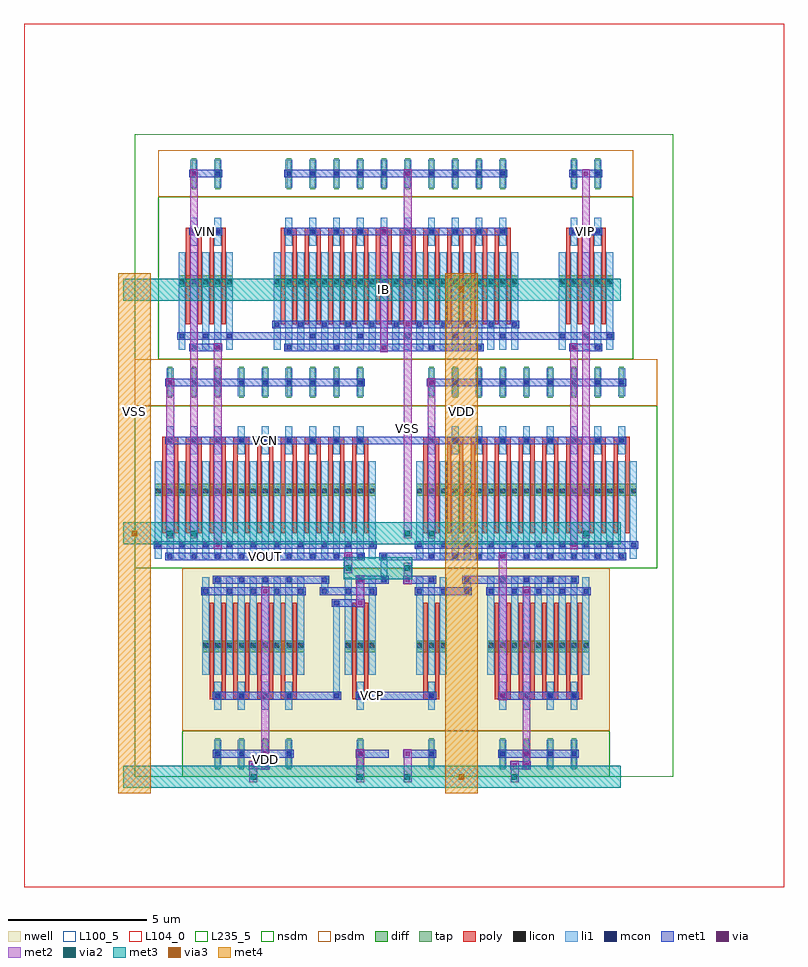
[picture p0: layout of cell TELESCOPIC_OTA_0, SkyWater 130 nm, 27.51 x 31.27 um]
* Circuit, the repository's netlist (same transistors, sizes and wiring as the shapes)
* NGSPICE file created from TELESCOPIC_OTA_0.ext - technology: sky130A

.subckt NMOS_4T_14241495_X2_Y1_1774869423 a_147_525# a_200_252# a_241_1232# a_230_525#
X0 a_230_525# a_200_252# a_147_525# a_241_1232# sky130_fd_pr__nfet_01v8 ad=0.0588 pd=0.7 as=0.0588 ps=0.7 w=0.42 l=0.15 M=4
.ends

.subckt PMOS_S_70514696_X4_Y1_1774869426 a_200_252# w_0_0# a_230_525#
X0 w_0_0# a_200_252# a_230_525# w_0_0# sky130_fd_pr__pfet_01v8 ad=0.0588 pd=0.7 as=0.0588 ps=0.7 w=0.42 l=0.15 M=8
.ends

.subckt NMOS_4T_34206428_X9_Y1_1774869424 a_147_525# a_200_252# a_241_1232# a_230_525#
X0 a_230_525# a_200_252# a_147_525# a_241_1232# sky130_fd_pr__nfet_01v8 ad=0.0588 pd=0.7 as=0.0588 ps=0.7 w=0.42 l=0.15 M=18
.ends

.subckt PMOS_4T_68898473_X1_Y1_1774869425 a_147_525# a_200_252# w_0_0# a_230_525#
X0 a_230_525# a_200_252# a_147_525# w_0_0# sky130_fd_pr__pfet_01v8 ad=0.0588 pd=0.7 as=0.1113 ps=1.37 w=0.42 l=0.15 M=2
.ends

.subckt SCM_NMOS_19423653_X5_Y1_1774869427 a_402_525# a_147_525# a_200_252#
X0 a_402_525# a_200_252# a_147_525# a_147_525# sky130_fd_pr__nfet_01v8 ad=0.0588 pd=0.7 as=0.0588 ps=0.7 w=0.42 l=0.15 M=10
X1 a_200_252# a_200_252# a_147_525# a_147_525# sky130_fd_pr__nfet_01v8 ad=0.0588 pd=0.7 as=0.0588 ps=0.7 w=0.42 l=0.15 M=10
.ends

.subckt TELESCOPIC_OTA_0 IB VCN VOUT VIP VIN VCP VSS VDD
XNMOS_4T_14241495_X2_Y1_1774869423_0 m1_688_3164# VIN VSS m1_570_1652# NMOS_4T_14241495_X2_Y1_1774869423
XNMOS_4T_14241495_X2_Y1_1774869423_1 m1_688_3164# VIP VSS m1_3150_1652# NMOS_4T_14241495_X2_Y1_1774869423
XPMOS_S_70514696_X4_Y1_1774869426_0 m1_2634_560# VDD li_2383_1327# PMOS_S_70514696_X4_Y1_1774869426
XPMOS_S_70514696_X4_Y1_1774869426_1 m1_2634_560# VDD li_1351_1327# PMOS_S_70514696_X4_Y1_1774869426
XNMOS_4T_34206428_X9_Y1_1774869424_0 m1_570_1652# VCN VSS VOUT NMOS_4T_34206428_X9_Y1_1774869424
XNMOS_4T_34206428_X9_Y1_1774869424_1 m1_3150_1652# VCN VSS m1_2634_560# NMOS_4T_34206428_X9_Y1_1774869424
XPMOS_4T_68898473_X1_Y1_1774869425_0 li_2383_1327# VCP VDD VOUT PMOS_4T_68898473_X1_Y1_1774869425
XPMOS_4T_68898473_X1_Y1_1774869425_1 li_1351_1327# VCP VDD m1_2634_560# PMOS_4T_68898473_X1_Y1_1774869425
XSCM_NMOS_19423653_X5_Y1_1774869427_0 m1_688_3164# VSS IB SCM_NMOS_19423653_X5_Y1_1774869427
.ends

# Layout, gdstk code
from math import pi, radians
import gdstk
lib = gdstk.Library(unit=1e-6, precision=1e-09)
def R(c, l, rs):  # rectangles x0, y0, x1, y1
    for r in rs: c.add(gdstk.rectangle(r[:2], r[2:], *l))
def A(c, l, x, y, w, h, nx, ny, dx, dy):  # array of equal rectangles
    R(c, l, [(x+i*dx, y+j*dy, x+i*dx+w, y+j*dy+h) for i in range(nx) for j in range(ny)])
def P(c, l, *ps):  # polygons
    for p in ps: c.add(gdstk.Polygon(p, *l))
nwell = (64, 20)
diff = (65, 20)
tap = (65, 44)
poly = (66, 20)
licon = (66, 44)
li1 = (67, 20)
mcon = (67, 44)
met1 = (68, 20)
via = (68, 44)
met2 = (69, 20)
via2 = (69, 44)
met3 = (70, 20)
via3 = (70, 44)
met4 = (71, 20)
nsdm = (93, 44)
psdm = (94, 20)
L100_5 = (100, 5)
L104_0 = (104, 0)
L235_5 = (235, 5)

scm_nmos_19423653_x5_y1_ = lib.new_cell('SCM_NMOS_19423653_X5_Y1_1774869427')
R(scm_nmos_19423653_x5_y1_, diff, [(0.735,2.625,9.585,3.045)])
A(scm_nmos_19423653_x5_y1_, tap, 1.205, 6.16, 0.17, 1.12, 10, 1, 0.86, 0)
A(scm_nmos_19423653_x5_y1_, poly, 1, 1.26, 0.15, 3.36, 20, 1, 0.43, 0)
A(scm_nmos_19423653_x5_y1_, poly, 1, 4.485, 0.58, 0.27, 10, 1, 0.86, 0)
A(scm_nmos_19423653_x5_y1_, licon, 0.775, 2.705, 0.17, 0.17, 3, 1, 0.43, 0)
A(scm_nmos_19423653_x5_y1_, licon, 1.635, 2.705, 0.17, 0.17, 3, 1, 0.43, 0)
A(scm_nmos_19423653_x5_y1_, licon, 2.495, 2.705, 0.17, 0.17, 3, 1, 0.43, 0)
A(scm_nmos_19423653_x5_y1_, licon, 3.355, 2.705, 0.17, 0.17, 3, 1, 0.43, 0)
A(scm_nmos_19423653_x5_y1_, licon, 4.215, 2.705, 0.17, 0.17, 3, 1, 0.43, 0)
A(scm_nmos_19423653_x5_y1_, licon, 5.075, 2.705, 0.17, 0.17, 3, 1, 0.43, 0)
A(scm_nmos_19423653_x5_y1_, licon, 5.935, 2.705, 0.17, 0.17, 3, 1, 0.43, 0)
A(scm_nmos_19423653_x5_y1_, licon, 6.795, 2.705, 0.17, 0.17, 3, 1, 0.43, 0)
A(scm_nmos_19423653_x5_y1_, licon, 7.655, 2.705, 0.17, 0.17, 3, 1, 0.43, 0)
A(scm_nmos_19423653_x5_y1_, licon, 8.515, 2.705, 0.17, 0.17, 3, 1, 0.43, 0)
A(scm_nmos_19423653_x5_y1_, licon, 1.205, 4.535, 0.17, 0.17, 10, 2, 0.86, 2.1)
A(scm_nmos_19423653_x5_y1_, li1, 0.735, 0.335, 0.25, 3.53, 21, 1, 0.43, 0)
A(scm_nmos_19423653_x5_y1_, li1, 1.165, 4.115, 0.25, 1.01, 10, 2, 0.86, 2.1)
A(scm_nmos_19423653_x5_y1_, mcon, 1.205, 0.335, 0.17, 0.17, 5, 1, 1.72, 0)
A(scm_nmos_19423653_x5_y1_, mcon, 2.065, 0.755, 0.17, 0.17, 5, 1, 1.72, 0)
A(scm_nmos_19423653_x5_y1_, mcon, 0.775, 1.175, 0.17, 0.17, 11, 1, 0.86, 0)
A(scm_nmos_19423653_x5_y1_, mcon, 1.205, 4.535, 0.17, 0.17, 10, 2, 0.86, 2.1)
R(scm_nmos_19423653_x5_y1_, met1, [(1.12,0.28,8.34,0.56), (1.98,0.7,9.2,0.98), (0.69,1.12,9.63,1.4), (1.12,4.48,9.2,4.76), (1.12,6.58,9.2,6.86)])
R(scm_nmos_19423653_x5_y1_, via, [(4.655,0.345,4.805,0.495), (5.515,1.185,5.665,1.335), (4.655,4.545,4.805,4.695), (5.515,6.645,5.665,6.795)])
R(scm_nmos_19423653_x5_y1_, met2, [(4.59,0.26,4.87,4.78), (5.45,1.1,5.73,6.88)])
R(scm_nmos_19423653_x5_y1_, nsdm, [(0,0,10.32,5.88)])
R(scm_nmos_19423653_x5_y1_, psdm, [(0,5.88,10.32,7.56)])
R(scm_nmos_19423653_x5_y1_, L100_5, [(0,0,10.32,7.56)])

pmos_s_70514696_x4_y1_17 = lib.new_cell('PMOS_S_70514696_X4_Y1_1774869426')
R(pmos_s_70514696_x4_y1_17, nwell, [(0,0,5.16,7.56)])
R(pmos_s_70514696_x4_y1_17, diff, [(0.735,2.625,4.425,3.045)])
A(pmos_s_70514696_x4_y1_17, tap, 1.205, 6.16, 0.17, 1.12, 4, 1, 0.86, 0)
A(pmos_s_70514696_x4_y1_17, poly, 1, 1.26, 0.15, 3.36, 8, 1, 0.43, 0)
A(pmos_s_70514696_x4_y1_17, poly, 1, 4.485, 0.58, 0.27, 4, 1, 0.86, 0)
A(pmos_s_70514696_x4_y1_17, licon, 0.775, 2.705, 0.17, 0.17, 3, 1, 0.43, 0)
A(pmos_s_70514696_x4_y1_17, licon, 1.635, 2.705, 0.17, 0.17, 3, 1, 0.43, 0)
A(pmos_s_70514696_x4_y1_17, licon, 2.495, 2.705, 0.17, 0.17, 3, 1, 0.43, 0)
A(pmos_s_70514696_x4_y1_17, licon, 3.355, 2.705, 0.17, 0.17, 3, 1, 0.43, 0)
A(pmos_s_70514696_x4_y1_17, licon, 1.205, 4.535, 0.17, 0.17, 4, 2, 0.86, 2.1)
A(pmos_s_70514696_x4_y1_17, li1, 0.735, 0.335, 0.25, 3.53, 9, 1, 0.43, 0)
A(pmos_s_70514696_x4_y1_17, li1, 1.165, 4.115, 0.25, 1.01, 4, 2, 0.86, 2.1)
A(pmos_s_70514696_x4_y1_17, mcon, 1.205, 0.335, 0.17, 0.17, 4, 2, 0.86, 4.2)
A(pmos_s_70514696_x4_y1_17, mcon, 0.775, 0.755, 0.17, 0.17, 5, 1, 0.86, 0)
A(pmos_s_70514696_x4_y1_17, mcon, 1.205, 6.635, 0.17, 0.17, 4, 1, 0.86, 0)
R(pmos_s_70514696_x4_y1_17, met1, [(1.12,0.28,4.04,0.56), (0.69,0.7,4.47,0.98), (1.12,4.48,4.04,4.76), (1.12,6.58,4.04,6.86)])
R(pmos_s_70514696_x4_y1_17, via, [(2.935,0.765,3.085,0.915), (2.935,6.645,3.085,6.795)])
R(pmos_s_70514696_x4_y1_17, met2, [(2.87,0.68,3.15,6.88)])
R(pmos_s_70514696_x4_y1_17, nsdm, [(0,5.88,5.16,7.56)])
R(pmos_s_70514696_x4_y1_17, psdm, [(0,0,5.16,5.88)])
R(pmos_s_70514696_x4_y1_17, L100_5, [(0,0,5.16,7.56)])

nmos_4t_34206428_x9_y1_1 = lib.new_cell('NMOS_4T_34206428_X9_Y1_1774869424')
R(nmos_4t_34206428_x9_y1_1, diff, [(0.735,2.625,8.725,3.045)])
A(nmos_4t_34206428_x9_y1_1, tap, 1.205, 6.16, 0.17, 1.12, 9, 1, 0.86, 0)
A(nmos_4t_34206428_x9_y1_1, poly, 1, 1.26, 0.15, 3.36, 18, 1, 0.43, 0)
A(nmos_4t_34206428_x9_y1_1, poly, 1, 4.485, 0.58, 0.27, 9, 1, 0.86, 0)
A(nmos_4t_34206428_x9_y1_1, licon, 0.775, 2.705, 0.17, 0.17, 3, 1, 0.43, 0)
A(nmos_4t_34206428_x9_y1_1, licon, 1.635, 2.705, 0.17, 0.17, 3, 1, 0.43, 0)
A(nmos_4t_34206428_x9_y1_1, licon, 2.495, 2.705, 0.17, 0.17, 3, 1, 0.43, 0)
A(nmos_4t_34206428_x9_y1_1, licon, 3.355, 2.705, 0.17, 0.17, 3, 1, 0.43, 0)
A(nmos_4t_34206428_x9_y1_1, licon, 4.215, 2.705, 0.17, 0.17, 3, 1, 0.43, 0)
A(nmos_4t_34206428_x9_y1_1, licon, 5.075, 2.705, 0.17, 0.17, 3, 1, 0.43, 0)
A(nmos_4t_34206428_x9_y1_1, licon, 5.935, 2.705, 0.17, 0.17, 3, 1, 0.43, 0)
A(nmos_4t_34206428_x9_y1_1, licon, 6.795, 2.705, 0.17, 0.17, 3, 1, 0.43, 0)
A(nmos_4t_34206428_x9_y1_1, licon, 7.655, 2.705, 0.17, 0.17, 3, 1, 0.43, 0)
A(nmos_4t_34206428_x9_y1_1, licon, 1.205, 4.535, 0.17, 0.17, 9, 2, 0.86, 2.1)
A(nmos_4t_34206428_x9_y1_1, li1, 0.735, 0.335, 0.25, 3.53, 19, 1, 0.43, 0)
A(nmos_4t_34206428_x9_y1_1, li1, 1.165, 4.115, 0.25, 1.01, 9, 2, 0.86, 2.1)
A(nmos_4t_34206428_x9_y1_1, mcon, 1.205, 0.335, 0.17, 0.17, 9, 2, 0.86, 4.2)
A(nmos_4t_34206428_x9_y1_1, mcon, 0.775, 0.755, 0.17, 0.17, 10, 1, 0.86, 0)
A(nmos_4t_34206428_x9_y1_1, mcon, 1.205, 6.635, 0.17, 0.17, 9, 1, 0.86, 0)
R(nmos_4t_34206428_x9_y1_1, met1, [(1.12,0.28,8.34,0.56), (0.69,0.7,8.77,0.98), (1.12,4.48,8.34,4.76), (1.12,6.58,8.34,6.86)])
R(nmos_4t_34206428_x9_y1_1, nsdm, [(0,0,9.46,5.88)])
R(nmos_4t_34206428_x9_y1_1, psdm, [(0,5.88,9.46,7.56)])
R(nmos_4t_34206428_x9_y1_1, L100_5, [(0,0,9.46,7.56)])

nmos_4t_14241495_x2_y1_1 = lib.new_cell('NMOS_4T_14241495_X2_Y1_1774869423')
R(nmos_4t_14241495_x2_y1_1, diff, [(0.735,2.625,2.705,3.045)])
R(nmos_4t_14241495_x2_y1_1, tap, [(1.205,6.16,1.375,7.28), (2.065,6.16,2.235,7.28)])
A(nmos_4t_14241495_x2_y1_1, poly, 1, 1.26, 0.15, 3.36, 4, 1, 0.43, 0)
R(nmos_4t_14241495_x2_y1_1, poly, [(1,4.485,1.58,4.755), (1.86,4.485,2.44,4.755)])
A(nmos_4t_14241495_x2_y1_1, licon, 0.775, 2.705, 0.17, 0.17, 3, 1, 0.43, 0)
A(nmos_4t_14241495_x2_y1_1, licon, 1.635, 2.705, 0.17, 0.17, 3, 1, 0.43, 0)
R(nmos_4t_14241495_x2_y1_1, licon, [(1.205,4.535,1.375,4.705), (2.065,4.535,2.235,4.705), (1.205,6.635,1.375,6.805), (2.065,6.635,2.235,6.805)])
A(nmos_4t_14241495_x2_y1_1, li1, 0.735, 0.335, 0.25, 3.53, 5, 1, 0.43, 0)
R(nmos_4t_14241495_x2_y1_1, li1, [(1.165,4.115,1.415,5.125), (2.025,4.115,2.275,5.125), (1.165,6.215,1.415,7.225), (2.025,6.215,2.275,7.225)])
A(nmos_4t_14241495_x2_y1_1, mcon, 0.775, 0.755, 0.17, 0.17, 3, 1, 0.86, 0)
R(nmos_4t_14241495_x2_y1_1, mcon, [(1.205,0.335,1.375,0.505), (2.065,0.335,2.235,0.505), (1.205,4.535,1.375,4.705), (2.065,4.535,2.235,4.705), (1.205,6.635,1.375,6.805), (2.065,6.635,2.235,6.805)])
R(nmos_4t_14241495_x2_y1_1, met1, [(1.12,0.28,2.32,0.56), (0.69,0.7,2.75,0.98), (1.12,4.48,2.32,4.76), (1.12,6.58,2.32,6.86)])
R(nmos_4t_14241495_x2_y1_1, nsdm, [(0,0,3.44,5.88)])
R(nmos_4t_14241495_x2_y1_1, psdm, [(0,5.88,3.44,7.56)])
R(nmos_4t_14241495_x2_y1_1, L100_5, [(0,0,3.44,7.56)])

pmos_4t_68898473_x1_y1_1 = lib.new_cell('PMOS_4T_68898473_X1_Y1_1774869425')
R(pmos_4t_68898473_x1_y1_1, nwell, [(0,0,2.58,7.56)])
R(pmos_4t_68898473_x1_y1_1, diff, [(0.735,2.625,1.845,3.045)])
R(pmos_4t_68898473_x1_y1_1, tap, [(1.205,6.16,1.375,7.28)])
R(pmos_4t_68898473_x1_y1_1, poly, [(1,1.26,1.15,4.62), (1.43,1.26,1.58,4.62), (1,4.485,1.58,4.755)])
A(pmos_4t_68898473_x1_y1_1, licon, 0.775, 2.705, 0.17, 0.17, 3, 1, 0.43, 0)
R(pmos_4t_68898473_x1_y1_1, licon, [(1.205,4.535,1.375,4.705), (1.205,6.635,1.375,6.805)])
A(pmos_4t_68898473_x1_y1_1, li1, 0.735, 0.335, 0.25, 3.53, 3, 1, 0.43, 0)
R(pmos_4t_68898473_x1_y1_1, li1, [(1.165,4.115,1.415,5.125), (1.165,6.215,1.415,7.225)])
R(pmos_4t_68898473_x1_y1_1, mcon, [(1.205,0.335,1.375,0.505), (0.775,0.755,0.945,0.925), (1.635,0.755,1.805,0.925), (1.205,4.535,1.375,4.705), (1.205,6.635,1.375,6.805)])
R(pmos_4t_68898473_x1_y1_1, met1, [(0.26,0.28,1.46,0.56), (0.69,0.7,1.89,0.98), (0.26,4.48,1.46,4.76), (0.26,6.58,1.46,6.86)])
R(pmos_4t_68898473_x1_y1_1, nsdm, [(0,5.88,2.58,7.56)])
R(pmos_4t_68898473_x1_y1_1, psdm, [(0,0,2.58,5.88)])
R(pmos_4t_68898473_x1_y1_1, L100_5, [(0,0,2.58,7.56)])

telescopic_ota_0 = lib.new_cell('TELESCOPIC_OTA_0')
R(telescopic_ota_0, li1, [(7.185,2.855,7.435,3.025), (7.185,2.855,7.435,3.025), (7.185,2.855,7.435,3.025), (7.185,2.855,7.435,3.025), (7.185,2.855,7.435,3.025), (7.185,2.855,7.435,3.025), (7.185,2.94,7.435,6.3), (7.185,6.215,7.435,6.385), (7.185,6.215,7.435,6.385), (7.185,6.215,7.435,6.385), (7.185,6.215,7.435,6.385), (7.185,6.215,7.435,6.385), (7.185,6.215,7.435,6.385), (6.755,6.635,7.005,6.805), (6.755,6.635,7.005,6.805), (11.915,6.635,12.165,6.805), (11.915,6.635,12.165,6.805), (6.755,6.72,7.005,7.14), (11.915,6.72,12.165,7.14), (6.755,7.055,7.005,7.225), (6.755,7.055,7.005,7.225), (8.905,7.055,9.155,7.225), (8.905,7.055,9.155,7.225), (8.905,7.055,9.155,7.225), (8.905,7.055,9.155,7.225), (11.915,7.055,12.165,7.225), (11.915,7.055,12.165,7.225), (8.905,7.14,9.155,7.98), (8.905,7.895,9.155,8.065), (8.905,7.895,9.155,8.065), (8.905,7.895,9.155,8.065), (8.905,7.895,9.155,8.065)])
R(telescopic_ota_0, mcon, [(7.225,2.855,7.395,3.025), (7.225,2.855,7.395,3.025), (7.225,2.855,7.395,3.025), (7.225,2.855,7.395,3.025), (7.225,2.855,7.395,3.025), (7.225,2.855,7.395,3.025), (7.225,6.215,7.395,6.385), (7.225,6.215,7.395,6.385), (7.225,6.215,7.395,6.385), (7.225,6.215,7.395,6.385), (7.225,6.215,7.395,6.385), (7.225,6.215,7.395,6.385), (6.795,6.635,6.965,6.805), (6.795,6.635,6.965,6.805), (11.955,6.635,12.125,6.805), (11.955,6.635,12.125,6.805), (6.795,7.055,6.965,7.225), (6.795,7.055,6.965,7.225), (8.945,7.055,9.115,7.225), (8.945,7.055,9.115,7.225), (8.945,7.055,9.115,7.225), (8.945,7.055,9.115,7.225), (11.955,7.055,12.125,7.225), (11.955,7.055,12.125,7.225), (8.945,7.895,9.115,8.065), (8.945,7.895,9.115,8.065), (8.945,7.895,9.115,8.065), (8.945,7.895,9.115,8.065)])
R(telescopic_ota_0, met1, [(4.14,0.28,4.46,0.56), (4.14,0.28,4.46,0.56), (4.14,0.28,4.46,0.56), (4.14,0.28,4.46,0.56), (4.14,0.28,4.46,0.56), (4.3,0.28,4.73,0.56), (4.57,0.28,4.89,0.56), (4.57,0.28,4.89,0.56), (4.57,0.28,4.89,0.56), (4.57,0.28,4.89,0.56), (4.57,0.28,4.89,0.56), (13.6,0.28,13.92,0.56), (13.6,0.28,13.92,0.56), (13.6,0.28,13.92,0.56), (13.6,0.28,13.92,0.56), (13.76,0.28,14.19,0.56), (14.03,0.28,14.35,0.56), (14.03,0.28,14.35,0.56), (14.03,0.28,14.35,0.56), (14.03,0.28,14.35,0.56), (8.01,0.7,8.33,0.98), (8.01,0.7,8.33,0.98), (8.01,0.7,8.33,0.98), (9.73,0.7,10.05,0.98), (9.73,0.7,10.05,0.98), (5.59,2.8,7.31,3.08), (7.14,2.8,7.48,3.08), (7.14,2.8,7.48,3.08), (7.14,2.8,7.48,3.08), (7.14,2.8,7.48,3.08), (7.14,2.8,7.48,3.08), (7.14,2.8,7.48,3.08), (9.03,2.8,9.89,3.08), (13.17,2.8,13.49,3.08), (13.17,2.8,13.49,3.08), (7.14,6.16,7.48,6.44), (7.14,6.16,7.48,6.44), (7.14,6.16,7.48,6.44), (7.14,6.16,7.48,6.44), (7.14,6.16,7.48,6.44), (7.14,6.16,7.48,6.44), (7.31,6.16,8.17,6.44), (8.01,6.16,8.33,6.44), (8.01,6.16,8.33,6.44), (8.01,6.16,8.33,6.44), (8.01,6.16,8.33,6.44), (8.01,6.16,8.33,6.44), (8.01,6.16,8.33,6.44), (6.71,6.58,7.05,6.86), (6.71,6.58,7.05,6.86), (6.88,6.58,7.74,6.86), (11.18,6.58,12.04,6.86), (11.87,6.58,12.21,6.86), (11.87,6.58,12.21,6.86), (5.59,7,6.88,7.28), (6.71,7,7.05,7.28), (6.71,7,7.05,7.28), (8.01,7,8.33,7.28), (8.01,7,8.33,7.28), (8.01,7,8.33,7.28), (8.01,7,8.33,7.28), (8.01,7,8.33,7.28), (8.01,7,8.33,7.28), (8.86,7,9.2,7.28), (8.86,7,9.2,7.28), (8.86,7,9.2,7.28), (8.86,7,9.2,7.28), (9.73,7,10.05,7.28), (9.73,7,10.05,7.28), (11.87,7,12.21,7.28), (11.87,7,12.21,7.28), (12.04,7,13.33,7.28), (7.58,7.84,7.9,8.12), (7.58,7.84,7.9,8.12), (8.86,7.84,9.2,8.12), (8.86,7.84,9.2,8.12), (8.86,7.84,9.2,8.12), (8.86,7.84,9.2,8.12), (9.03,7.84,10.75,8.12), (13.17,7.84,13.49,8.12), (13.17,7.84,13.49,8.12), (2.85,8.26,3.17,8.54), (2.85,8.26,3.17,8.54), (15.75,8.26,16.07,8.54), (15.75,8.26,16.07,8.54), (8.17,12.04,10.75,12.32), (1.13,14.14,1.45,14.42), (1.13,14.14,1.45,14.42), (1.13,14.14,1.45,14.42), (1.13,14.14,1.45,14.42), (10.59,14.14,10.91,14.42), (10.59,14.14,10.91,14.42), (10.59,14.14,10.91,14.42), (10.59,14.14,10.91,14.42), (10.59,14.14,10.91,14.42), (2.85,15.4,3.17,15.68), (2.85,15.4,3.17,15.68), (15.75,15.4,16.07,15.68), (15.75,15.4,16.07,15.68), (3.44,15.82,6.45,16.1), (13.33,15.82,15.48,16.1), (1.99,21.7,2.31,21.98), (1.99,21.7,2.31,21.98), (16.18,21.7,16.5,21.98), (16.18,21.7,16.5,21.98), (16.18,21.7,16.5,21.98)])
P(telescopic_ota_0, met1, [(0,0),(0,0),(0,0),(0,0)],
  [(0,0),(0,0),(0,0),(0,0)],
  [(0,0),(0,0),(0,0),(0,0)],
  [(0,0),(0,0),(0,0),(0,0)],
  [(0,0),(0,0),(0,0),(0,0)],
  [(0,0),(0,0),(0,0),(0,0)],
  [(0,0),(0,0),(0,0),(0,0)],
  [(0,0),(0,0),(0,0),(0,0)],
  [(0,0),(0,0),(0,0),(0,0)],
  [(0,0),(0,0),(0,0),(0,0)],
  [(0,0),(0,0),(0,0),(0,0)],
  [(0,0),(0,0),(0,0),(0,0)],
  [(0,0),(0,0),(0,0),(0,0)],
  [(0,0),(0,0),(0,0),(0,0)],
  [(0,0),(0,0),(0,0),(0,0)],
  [(0,0),(0,0),(0,0),(0,0)],
  [(0,0),(0,0),(0,0),(0,0)],
  [(0,0),(0,0),(0,0),(0,0)],
  [(0,0),(0,0),(0,0),(0,0)],
  [(0,0),(0,0),(0,0),(0,0)],
  [(0,0),(0,0),(0,0),(0,0)],
  [(0,0),(0,0),(0,0),(0,0)],
  [(0,0),(0,0),(0,0),(0,0)],
  [(0,0),(0,0),(0,0),(0,0)],
  [(0,0),(0,0),(0,0),(0,0)],
  [(0,0),(0,0),(0,0),(0,0)],
  [(0,0),(0,0),(0,0),(0,0)],
  [(0,0),(0,0),(0,0),(0,0)],
  [(0,0),(0,0),(0,0),(0,0)],
  [(0,0),(0,0),(0,0),(0,0)],
  [(0,0),(0,0),(0,0),(0,0)],
  [(0,0),(0,0),(0,0),(0,0)],
  [(0,0),(0,0),(0,0),(0,0)],
  [(0,0),(0,0),(0,0),(0,0)])
R(telescopic_ota_0, via, [(4.225,0.345,4.375,0.495), (4.225,0.345,4.375,0.495), (4.225,0.345,4.375,0.495), (4.225,0.345,4.375,0.495), (4.225,0.345,4.375,0.495), (4.655,0.345,4.805,0.495), (4.655,0.345,4.805,0.495), (4.655,0.345,4.805,0.495), (4.655,0.345,4.805,0.495), (4.655,0.345,4.805,0.495), (13.685,0.345,13.835,0.495), (13.685,0.345,13.835,0.495), (13.685,0.345,13.835,0.495), (13.685,0.345,13.835,0.495), (14.115,0.345,14.265,0.495), (14.115,0.345,14.265,0.495), (14.115,0.345,14.265,0.495), (14.115,0.345,14.265,0.495), (8.095,0.765,8.245,0.915), (8.095,0.765,8.245,0.915), (8.095,0.765,8.245,0.915), (9.815,0.765,9.965,0.915), (9.815,0.765,9.965,0.915), (13.255,2.865,13.405,3.015), (13.255,2.865,13.405,3.015), (8.095,6.225,8.245,6.375), (8.095,6.225,8.245,6.375), (8.095,6.225,8.245,6.375), (8.095,6.225,8.245,6.375), (8.095,6.225,8.245,6.375), (8.095,6.225,8.245,6.375), (8.095,7.065,8.245,7.215), (8.095,7.065,8.245,7.215), (8.095,7.065,8.245,7.215), (8.095,7.065,8.245,7.215), (8.095,7.065,8.245,7.215), (8.095,7.065,8.245,7.215), (9.815,7.065,9.965,7.215), (9.815,7.065,9.965,7.215), (7.665,7.905,7.815,8.055), (7.665,7.905,7.815,8.055), (13.255,7.905,13.405,8.055), (13.255,7.905,13.405,8.055), (2.935,8.325,3.085,8.475), (2.935,8.325,3.085,8.475), (15.835,8.325,15.985,8.475), (15.835,8.325,15.985,8.475), (1.215,14.205,1.365,14.355), (1.215,14.205,1.365,14.355), (1.215,14.205,1.365,14.355), (1.215,14.205,1.365,14.355), (10.675,14.205,10.825,14.355), (10.675,14.205,10.825,14.355), (10.675,14.205,10.825,14.355), (10.675,14.205,10.825,14.355), (10.675,14.205,10.825,14.355), (2.935,15.465,3.085,15.615), (2.935,15.465,3.085,15.615), (15.835,15.465,15.985,15.615), (15.835,15.465,15.985,15.615), (2.075,21.765,2.225,21.915), (2.075,21.765,2.225,21.915), (16.265,21.765,16.415,21.915), (16.265,21.765,16.415,21.915), (16.265,21.765,16.415,21.915)])
R(telescopic_ota_0, met2, [(4.16,-0.185,4.44,0.185), (4.16,-0.185,4.44,0.185), (4.16,-0.185,4.44,0.185), (4.16,-0.185,4.44,0.185), (4.16,-0.185,4.44,0.185), (8.03,-0.185,8.31,0.185), (8.03,-0.185,8.31,0.185), (8.03,-0.185,8.31,0.185), (9.75,-0.185,10.03,0.185), (9.75,-0.185,10.03,0.185), (13.62,-0.185,13.9,0.185), (13.62,-0.185,13.9,0.185), (13.62,-0.185,13.9,0.185), (13.62,-0.185,13.9,0.185), (4.16,0,4.44,0.42), (8.03,0,8.31,0.84), (9.75,0,10.03,0.84), (13.62,0,13.9,0.42), (4.16,0.26,4.44,0.58), (4.16,0.26,4.44,0.58), (4.16,0.26,4.44,0.58), (4.16,0.26,4.44,0.58), (4.16,0.26,4.44,0.58), (4.59,0.26,4.87,0.58), (4.59,0.26,4.87,0.58), (4.59,0.26,4.87,0.58), (4.59,0.26,4.87,0.58), (4.59,0.26,4.87,0.58), (13.62,0.26,13.9,0.58), (13.62,0.26,13.9,0.58), (13.62,0.26,13.9,0.58), (13.62,0.26,13.9,0.58), (14.05,0.26,14.33,0.58), (14.05,0.26,14.33,0.58), (14.05,0.26,14.33,0.58), (14.05,0.26,14.33,0.58), (4.59,0.42,4.87,0.84), (14.05,0.42,14.33,0.84), (8.03,0.68,8.31,1), (8.03,0.68,8.31,1), (8.03,0.68,8.31,1), (9.75,0.68,10.03,1), (9.75,0.68,10.03,1), (13.19,2.78,13.47,3.1), (13.19,2.78,13.47,3.1), (13.19,2.94,13.47,7.98), (8.03,6.14,8.31,6.46), (8.03,6.14,8.31,6.46), (8.03,6.14,8.31,6.46), (8.03,6.14,8.31,6.46), (8.03,6.14,8.31,6.46), (8.03,6.14,8.31,6.46), (8.03,6.3,8.31,7.14), (8.03,6.98,8.31,7.3), (8.03,6.98,8.31,7.3), (8.03,6.98,8.31,7.3), (8.03,6.98,8.31,7.3), (8.03,6.98,8.31,7.3), (8.03,6.98,8.31,7.3), (9.75,6.98,10.03,7.3), (9.75,6.98,10.03,7.3), (9.75,7.14,10.03,7.56), (7.6,7.375,7.88,7.745), (7.6,7.375,7.88,7.745), (9.75,7.375,10.03,7.745), (9.75,7.375,10.03,7.745), (7.6,7.56,7.88,7.98), (7.6,7.82,7.88,8.14), (7.6,7.82,7.88,8.14), (13.19,7.82,13.47,8.14), (13.19,7.82,13.47,8.14), (2.87,8.24,3.15,8.56), (2.87,8.24,3.15,8.56), (15.77,8.24,16.05,8.56), (15.77,8.24,16.05,8.56), (2.87,8.4,3.15,15.54), (15.77,8.4,16.05,15.54), (1.15,8.635,1.43,9.005), (1.15,8.635,1.43,9.005), (1.15,8.635,1.43,9.005), (1.15,8.635,1.43,9.005), (2.01,8.635,2.29,9.005), (2.01,8.635,2.29,9.005), (9.75,8.635,10.03,9.005), (9.75,8.635,10.03,9.005), (9.75,8.635,10.03,9.005), (9.75,8.635,10.03,9.005), (9.75,8.635,10.03,9.005), (9.75,8.635,10.03,9.005), (10.61,8.635,10.89,9.005), (10.61,8.635,10.89,9.005), (10.61,8.635,10.89,9.005), (10.61,8.635,10.89,9.005), (10.61,8.635,10.89,9.005), (16.2,8.635,16.48,9.005), (16.2,8.635,16.48,9.005), (16.2,8.635,16.48,9.005), (1.15,8.82,1.43,14.28), (2.01,8.82,2.29,21.84), (9.75,8.82,10.03,16.38), (10.61,8.82,10.89,14.28), (16.2,8.82,16.48,21.84), (1.15,14.12,1.43,14.44), (1.15,14.12,1.43,14.44), (1.15,14.12,1.43,14.44), (1.15,14.12,1.43,14.44), (10.61,14.12,10.89,14.44), (10.61,14.12,10.89,14.44), (10.61,14.12,10.89,14.44), (10.61,14.12,10.89,14.44), (10.61,14.12,10.89,14.44), (2.87,15.38,3.15,15.7), (2.87,15.38,3.15,15.7), (15.77,15.38,16.05,15.7), (15.77,15.38,16.05,15.7), (2.01,21.68,2.29,22), (2.01,21.68,2.29,22), (16.2,21.68,16.48,22), (16.2,21.68,16.48,22), (16.2,21.68,16.48,22)])
P(telescopic_ota_0, met2, [(0,0),(0,0),(0,0),(0,0)],
  [(0,0),(0,0),(0,0),(0,0)],
  [(0,0),(0,0),(0,0),(0,0)],
  [(0,0),(0,0),(0,0),(0,0)],
  [(0,0),(0,0),(0,0),(0,0)])
R(telescopic_ota_0, via2, [(4.2,-0.1,4.4,0.1), (4.2,-0.1,4.4,0.1), (4.2,-0.1,4.4,0.1), (4.2,-0.1,4.4,0.1), (4.2,-0.1,4.4,0.1), (8.07,-0.1,8.27,0.1), (8.07,-0.1,8.27,0.1), (8.07,-0.1,8.27,0.1), (9.79,-0.1,9.99,0.1), (9.79,-0.1,9.99,0.1), (13.66,-0.1,13.86,0.1), (13.66,-0.1,13.86,0.1), (13.66,-0.1,13.86,0.1), (13.66,-0.1,13.86,0.1), (7.64,7.46,7.84,7.66), (7.64,7.46,7.84,7.66), (9.79,7.46,9.99,7.66), (9.79,7.46,9.99,7.66), (1.19,8.72,1.39,8.92), (1.19,8.72,1.39,8.92), (1.19,8.72,1.39,8.92), (1.19,8.72,1.39,8.92), (2.05,8.72,2.25,8.92), (2.05,8.72,2.25,8.92), (9.79,8.72,9.99,8.92), (9.79,8.72,9.99,8.92), (9.79,8.72,9.99,8.92), (9.79,8.72,9.99,8.92), (9.79,8.72,9.99,8.92), (9.79,8.72,9.99,8.92), (10.65,8.72,10.85,8.92), (10.65,8.72,10.85,8.92), (10.65,8.72,10.85,8.92), (10.65,8.72,10.85,8.92), (10.65,8.72,10.85,8.92), (16.24,8.72,16.44,8.92), (16.24,8.72,16.44,8.92), (16.24,8.72,16.44,8.92)])
A(telescopic_ota_0, met3, -0.4, -0.4, 4.24, 0.8, 3, 3, 3.44, 8.82)
A(telescopic_ota_0, met3, 9.92, -0.4, 2.32, 0.8, 1, 3, 0, 8.82)
A(telescopic_ota_0, met3, 11.44, -0.4, 2.72, 0.8, 1, 3, 0, 8.82)
A(telescopic_ota_0, met3, 13.36, -0.4, 4.24, 0.8, 1, 3, 0, 8.82)
R(telescopic_ota_0, met3, [(4.135,-0.4,4.465,0.4), (4.135,-0.4,4.465,0.4), (4.135,-0.4,4.465,0.4), (4.135,-0.4,4.465,0.4), (4.135,-0.4,4.465,0.4), (8.005,-0.4,8.335,0.4), (8.005,-0.4,8.335,0.4), (8.005,-0.4,8.335,0.4), (9.725,-0.4,10.055,0.4), (9.725,-0.4,10.055,0.4), (11.675,-0.4,12.005,0.4), (13.595,-0.4,13.925,0.4), (13.595,-0.4,13.925,0.4), (13.595,-0.4,13.925,0.4), (13.595,-0.4,13.925,0.4), (7.575,7.16,7.905,7.96), (7.575,7.16,7.905,7.96), (7.74,7.16,9.89,7.96), (9.725,7.16,10.055,7.96), (9.725,7.16,10.055,7.96), (-0.165,8.42,0.165,9.22), (1.125,8.42,1.455,9.22), (1.125,8.42,1.455,9.22), (1.125,8.42,1.455,9.22), (1.125,8.42,1.455,9.22), (1.985,8.42,2.315,9.22), (1.985,8.42,2.315,9.22), (9.725,8.42,10.055,9.22), (9.725,8.42,10.055,9.22), (9.725,8.42,10.055,9.22), (9.725,8.42,10.055,9.22), (9.725,8.42,10.055,9.22), (9.725,8.42,10.055,9.22), (10.585,8.42,10.915,9.22), (10.585,8.42,10.915,9.22), (10.585,8.42,10.915,9.22), (10.585,8.42,10.915,9.22), (10.585,8.42,10.915,9.22), (16.175,8.42,16.505,9.22), (16.175,8.42,16.505,9.22), (16.175,8.42,16.505,9.22), (11.675,17.24,12.005,18.04)])
R(telescopic_ota_0, via3, [(11.74,-0.1,11.94,0.1), (-0.1,8.72,0.1,8.92), (11.74,17.54,11.94,17.74)])
R(telescopic_ota_0, met4, [(-0.59,-0.59,0.59,9.41), (11.25,-0.59,12.43,9.41), (11.25,-0.165,12.43,0.165), (-0.59,8.23,0.59,18.23), (11.25,8.23,12.43,18.23), (-0.59,8.655,0.59,8.985), (11.25,17.475,12.43,17.805)])
R(telescopic_ota_0, L104_0, [(-4,-4,23.51,27.27)])
R(telescopic_ota_0, L235_5, [(0,0,19.51,23.27)])
telescopic_ota_0.add(gdstk.Reference(scm_nmos_19423653_x5_y1_, (4.3,15.12)))
telescopic_ota_0.add(gdstk.Reference(pmos_s_70514696_x4_y1_17, (1.72,7.56), x_reflection=True))
telescopic_ota_0.add(gdstk.Reference(pmos_s_70514696_x4_y1_17, (17.2,7.56), rotation=pi))
telescopic_ota_0.add(gdstk.Reference(nmos_4t_34206428_x9_y1_1, (18.92,7.56), rotation=pi, x_reflection=True))
telescopic_ota_0.add(gdstk.Reference(nmos_4t_34206428_x9_y1_1, (0,7.56)))
telescopic_ota_0.add(gdstk.Reference(nmos_4t_14241495_x2_y1_1, (14.62,15.12)))
telescopic_ota_0.add(gdstk.Reference(nmos_4t_14241495_x2_y1_1, (4.3,15.12), rotation=pi, x_reflection=True))
telescopic_ota_0.add(gdstk.Reference(pmos_4t_68898473_x1_y1_1, (9.46,7.56), rotation=pi))
telescopic_ota_0.add(gdstk.Reference(pmos_4t_68898473_x1_y1_1, (9.46,7.56), x_reflection=True))
telescopic_ota_0.add(gdstk.Label('IB', (9.03,17.64), layer=69, texttype=5))
telescopic_ota_0.add(gdstk.Label('VCN', (4.73,12.18), layer=68, texttype=5))
telescopic_ota_0.add(gdstk.Label('VOUT', (4.73,7.98), layer=68, texttype=5))
telescopic_ota_0.add(gdstk.Label('VIP', (16.34,19.74), layer=68, texttype=5))
telescopic_ota_0.add(gdstk.Label('VIN', (2.58,19.74), layer=68, texttype=5))
telescopic_ota_0.add(gdstk.Label('VCP', (8.6,2.94), layer=68, texttype=5))
telescopic_ota_0.add(gdstk.Label('VSS', (9.89,12.6), layer=69, texttype=5))
telescopic_ota_0.add(gdstk.Label('VSS', (0,13.23), layer=71, texttype=5))
telescopic_ota_0.add(gdstk.Label('VSS', (0,13.23), layer=71, texttype=5))
telescopic_ota_0.add(gdstk.Label('VSS', (0,13.23), layer=71, texttype=5))
telescopic_ota_0.add(gdstk.Label('VSS', (0,13.23), layer=71, texttype=5))
telescopic_ota_0.add(gdstk.Label('VSS', (0,13.23), layer=71, texttype=5))
telescopic_ota_0.add(gdstk.Label('VSS', (0,13.23), layer=71, texttype=5))
telescopic_ota_0.add(gdstk.Label('VSS', (0,13.23), layer=71, texttype=5))
telescopic_ota_0.add(gdstk.Label('VSS', (0,13.23), layer=71, texttype=5))
telescopic_ota_0.add(gdstk.Label('VSS', (0,13.23), layer=71, texttype=5))
telescopic_ota_0.add(gdstk.Label('VSS', (0,13.23), layer=71, texttype=5))
telescopic_ota_0.add(gdstk.Label('VSS', (0,13.23), layer=71, texttype=5))
telescopic_ota_0.add(gdstk.Label('VSS', (0,13.23), layer=71, texttype=5))
telescopic_ota_0.add(gdstk.Label('VSS', (0,13.23), layer=71, texttype=5))
telescopic_ota_0.add(gdstk.Label('VSS', (0,13.23), layer=71, texttype=5))
telescopic_ota_0.add(gdstk.Label('VDD', (4.73,0.63), layer=69, texttype=5))
telescopic_ota_0.add(gdstk.Label('VDD', (11.84,13.23), layer=71, texttype=5))
telescopic_ota_0.add(gdstk.Label('VDD', (11.84,13.23), layer=71, texttype=5))
telescopic_ota_0.add(gdstk.Label('VDD', (11.84,13.23), layer=71, texttype=5))
telescopic_ota_0.add(gdstk.Label('VDD', (11.84,13.23), layer=71, texttype=5))
telescopic_ota_0.add(gdstk.Label('VDD', (11.84,13.23), layer=71, texttype=5))
telescopic_ota_0.add(gdstk.Label('VDD', (11.84,13.23), layer=71, texttype=5))
telescopic_ota_0.add(gdstk.Label('VDD', (11.84,13.23), layer=71, texttype=5))
telescopic_ota_0.add(gdstk.Label('VDD', (11.84,13.23), layer=71, texttype=5))
telescopic_ota_0.add(gdstk.Label('VDD', (11.84,13.23), layer=71, texttype=5))
telescopic_ota_0.add(gdstk.Label('VDD', (11.84,13.23), layer=71, texttype=5))
telescopic_ota_0.add(gdstk.Label('VDD', (11.84,13.23), layer=71, texttype=5))
telescopic_ota_0.add(gdstk.Label('VDD', (11.84,13.23), layer=71, texttype=5))
telescopic_ota_0.add(gdstk.Label('VDD', (11.84,13.23), layer=71, texttype=5))
telescopic_ota_0.add(gdstk.Label('VDD', (11.84,13.23), layer=71, texttype=5))

lib.write_gds('TELESCOPIC_OTA_0.gds')
